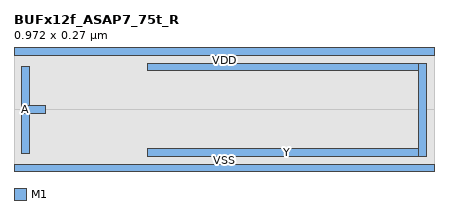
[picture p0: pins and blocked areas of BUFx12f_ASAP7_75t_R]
MACRO BUFx12f_ASAP7_75t_R
  CLASS CORE ;
  ORIGIN 0 0 ;
  FOREIGN BUFx12f_ASAP7_75t_R 0 0 ;
  SIZE 0.972 BY 0.27 ;
  SYMMETRY X Y ;
  SITE asap7sc7p5t ;
  PIN A
    DIRECTION INPUT ;
    USE SIGNAL ;
    PORT
      LAYER M1 ;
        RECT 0.018 0.126 0.074 0.144 ;
        RECT 0.018 0.034 0.036 0.236 ;
    END
  END A
  PIN VDD
    DIRECTION INOUT ;
    USE POWER ;
    SHAPE ABUTMENT ;
    PORT
      LAYER M1 ;
        RECT 0 0.261 0.972 0.279 ;
    END
  END VDD
  PIN VSS
    DIRECTION INOUT ;
    USE GROUND ;
    SHAPE ABUTMENT ;
    PORT
      LAYER M1 ;
        RECT 0 -0.009 0.972 0.009 ;
    END
  END VSS
  PIN Y
    DIRECTION OUTPUT ;
    USE SIGNAL ;
    PORT
      LAYER M1 ;
        RECT 0.31 0.225 0.954 0.243 ;
        RECT 0.936 0.027 0.954 0.243 ;
        RECT 0.31 0.027 0.954 0.045 ;
    END
  END Y
  OBS
    LAYER M1 ;
      RECT 0.094 0.225 0.279 0.243 ;
      RECT 0.261 0.027 0.279 0.243 ;
      RECT 0.261 0.126 0.311 0.144 ;
      RECT 0.094 0.027 0.279 0.045 ;
		LAYER RVTN ;
			RECT 0 0 0.972 0.135 ;
		LAYER RVTP ;
			RECT 0 0.135 0.972 0.27 ;
  END
END BUFx12f_ASAP7_75t_R
